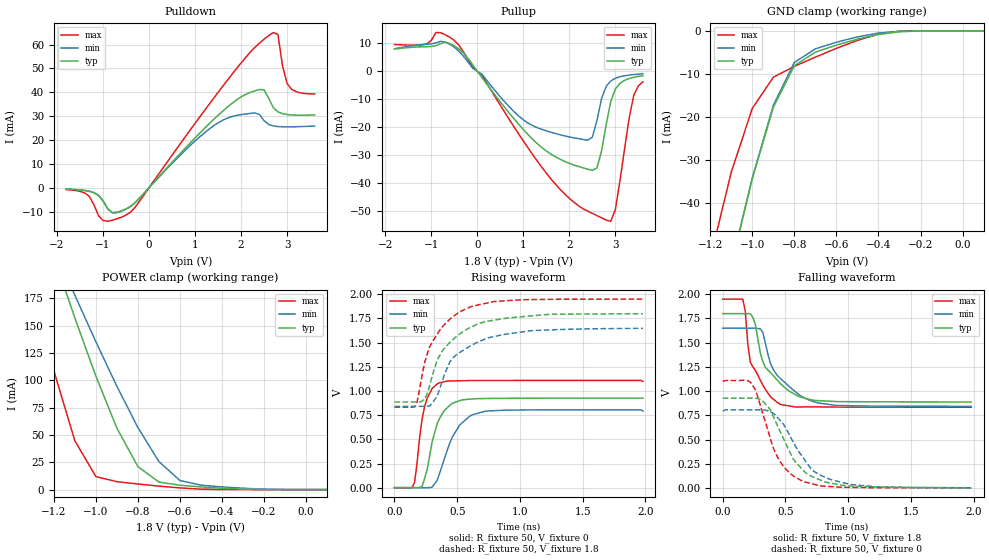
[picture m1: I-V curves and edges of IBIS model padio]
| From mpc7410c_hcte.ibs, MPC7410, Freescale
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| *   padio Model   *
[Model]   padio
Model_type   I/O
Polarity   Non-Inverting
Vinl = 0.63V
Vinh = 1.17V
Vmeas = 0.9V
Cref = 0
Rref = 50
Vref = 0.9V
|   typ   min   max
C_comp   2.563220e-12   2.204270e-12   2.663340e-12
|   typ   min   max
[Voltage range]   1.8V   1.65V   1.95V
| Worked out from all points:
|   slope of the pulldown table from 0 to 0.27 V, typ, clamps not added: 46.5 ohm
|   slope of the pullup table from 0 to 0.27 V, typ, clamps not added: 44.9 ohm
|   GND clamp passes 1 mA (typ) near -0.41 V on its own axis
|   POWER clamp passes 1 mA (typ) near -0.37 V on its own axis
|   falling waveform, R_fixture 50, V_fixture 1.8: 20-80 % time 196ps typ, 228ps min, 136ps max; typ from 1.8 V to 0.888 V
|   rising waveform, R_fixture 50, V_fixture 0: 20-80 % time 110ps typ, 151ps min, 73.6ps max; typ from 0.002 V to 0.926 V
|   falling waveform, R_fixture 50, V_fixture 0: 20-80 % time 237ps typ, 245ps min, 192ps max; typ from 0.926 V to 0.001 V
|   rising waveform, R_fixture 50, V_fixture 1.8: 20-80 % time 268ps typ, 278ps min, 223ps max; typ from 0.887 V to 1.8 V
[Pulldown]
|   Voltage   I(typ)   I(min)   I(max)
-1.8V     -606.8uA   -603.4uA   -802.4uA
-1.3V     -1.514mA   -1.486mA   -3.621mA
-1V       -5.639mA   -5.432mA   -13.74mA
-800mV    -10.41mA   -10.58mA   -13.67mA
-400mV    -7.822mA   -7.832mA   -10.21mA
1.5V      30.35mA    27.21mA    39.97mA
2.4V      41.16mA    30.67mA    60.6mA
2.7V      33.55mA    25.9mA     65.05mA
2.8V      31.81mA    25.64mA    64.3mA
2.9V      31.03mA    25.54mA    51.09mA
3V        30.66mA    25.51mA    43.69mA
3.6V      30.5mA     25.86mA    39.3mA
[GND_clamp]
-1.8V     -232mA     -232mA     -208.4mA
-1.2V     -76.69mA   -76.65mA   -52.94mA
-1.1V     -54.53mA   -54.43mA   -32.84mA
-1V       -34.39mA   -34.17mA   -18.02mA
-900mV    -17.76mA   -17.27mA   -10.79mA
-800mV    -8.1mA     -7.349mA   -8.261mA
-700mV    -4.948mA   -4.19mA    -6.115mA
-600mV    -3.315mA   -2.652mA   -4.077mA
-500mV    -1.938mA   -1.413mA   -2.223mA
-400mV    -849.8uA   -524.9uA   -765.8uA
-300mV    -218.8uA   -102.3uA   -83.96uA
100mV     0A         0A         0A
[Pullup]
-1.8V     7.912mA    8.018mA    9.503mA
-1.1V     8.739mA    9.607mA    9.735mA
-900mV    9.089mA    10.08mA    13.78mA
-500mV    9.035mA    8.552mA    10.97mA
1.1V      -22.59mA   -18.5mA    -27.33mA
1.9V      -32.2mA    -23.09mA   -43.83mA
2.5V      -35.4mA    -23.56mA   -50.72mA
2.7V      -28.47mA   -9.812mA   -52.34mA
2.9V      -10.78mA   -3.501mA   -53.57mA
3V        -6.349mA   -2.546mA   -49.42mA
3.4V      -2.185mA   -1.2mA     -8.597mA
3.6V      -1.636mA   -916.1uA   -3.783mA
[POWER_clamp]
-1.8V     573.2mA    491.9mA    598mA
-1.3V     271.2mA    265.4mA    183.9mA
-1.2V     213.2mA    221.2mA    108.8mA
-1.1V     157mA      177.7mA    44.67mA
-1V       103.7mA    135.2mA    11.86mA
-900mV    56.2mA     94.41mA    7.249mA
-800mV    20.97mA    56.73mA    5.115mA
-700mV    6.889mA    25.59mA    3.192mA
-600mV    4mA        8.298mA    1.547mA
-500mV    2.461mA    4.058mA    417.2uA
-300mV    412.1uA    1.268mA    2.246uA
100mV     0A         0A         0A
|   typ   min   max
[Ramp]
dV/dt_r   0.55489/1.10054e-10   0.48274/1.54952e-10   0.66523/7.35359e-11
dV/dt_f   0.54755/1.96657e-10   0.48461/2.28787e-10   0.66997/1.35857e-10
[Falling Waveform]
R_fixture = 50
V_fixture = 1.8
V_fixture_min = 1.65
V_fixture_max = 1.95
| time   V(typ)   V(min)   V(max)
0s        1.8V       1.65V      1.95V
160ps     1.8V       1.65V      1.949V
180ps     1.8V       1.65V      1.823V
220ps     1.8V       1.65V      1.299V
260ps     1.69V      1.651V     1.213V
320ps     1.304V     1.605V     1.061V
380ps     1.192V     1.29V      942.8mV
460ps     1.078V     1.13V      862.2mV
780ps     901.1mV    874.2mV    836.7mV
1.98ns    888.2mV    843.1mV    833.8mV
[Rising Waveform]
R_fixture = 50
V_fixture = 0
V_fixture_min = 0
V_fixture_max = 0
| time   V(typ)   V(min)   V(max)
0s        1.682mV    1.824mV    1.051mV
140ps     1.435mV    1.671mV    1.542mV
160ps     763.5uV    1.661mV    56.07mV
200ps     2.647mV    1.502mV    515.2mV
240ps     95.07mV    219.6uV    837mV
300ps     474.4mV    6.536mV    1.027V
360ps     719.1mV    149.6mV    1.086V
460ps     873.6mV    522.9mV    1.104V
620ps     918mV      754.6mV    1.109V
1.98ns    926.5mV    794.3mV    1.1V
[Falling Waveform]
R_fixture = 50
V_fixture = 0
V_fixture_min = 0
V_fixture_max = 0
| time   V(typ)   V(min)   V(max)
0s        926.5mV    794.3mV    1.1V
220ps     927.9mV    806.4mV    1.093V
260ps     928mV      807mV      1.015V
320ps     895.4mV    807.4mV    765.5mV
440ps     633mV      722.5mV    311.5mV
560ps     302.5mV    478.5mV    126.7mV
640ps     184.6mV    314mV      66.57mV
760ps     91.92mV    145.8mV    27.21mV
1.02ns    20.09mV    36.39mV    5.983mV
1.98ns    1.142mV    2.478mV    1.209mV
[Rising Waveform]
R_fixture = 50
V_fixture = 1.8
V_fixture_min = 1.65
V_fixture_max = 1.95
| time   V(typ)   V(min)   V(max)
0s        887.4mV    842.3mV    833.4mV
160ps     887.3mV    842.1mV    837.3mV
180ps     887.2mV    842.1mV    886mV
240ps     920.8mV    842mV      1.293V
280ps     1.057V     845.2mV    1.457V
380ps     1.412V     1.101V     1.662V
460ps     1.526V     1.336V     1.763V
600ps     1.654V     1.463V     1.867V
1.08ns    1.775V     1.623V     1.945V
1.98ns    1.799V     1.648V     1.95V
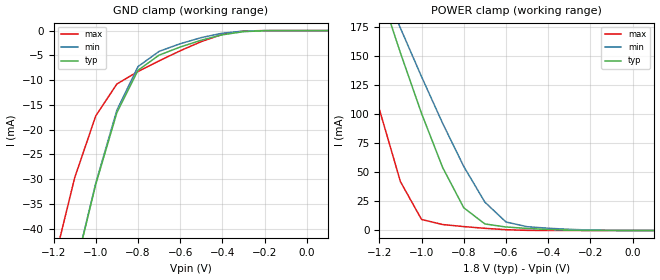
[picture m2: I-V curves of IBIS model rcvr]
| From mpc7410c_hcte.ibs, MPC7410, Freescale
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| *   rcvr  Model   *
[Model]   rcvr
Model_type   Input
Polarity   Non-Inverting
Vinl =   0.63V
Vinh =   1.17V
|   typ   min   max
C_comp   1.925330e-12   1.688180e-12   2.015310e-12
|   typ   min   max
[Voltage range]   1.8V   1.65V   1.95V
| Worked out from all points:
|   GND clamp passes 1 mA (typ) near -0.41 V on its own axis
|   POWER clamp passes 1 mA (typ) near -0.42 V on its own axis
|   Voltage(V)   I(typ)   I(min)   I(max)
[GND_clamp]
-1.8V     -206.6mA   -206.6mA   -185.7mA
-1.2V     -68.14mA   -68.09mA   -47.21mA
-1.1V     -48.65mA   -48.53mA   -29.75mA
-1V       -31.06mA   -30.82mA   -17.23mA
-900mV    -16.58mA   -16.09mA   -10.79mA
-800mV    -8.028mA   -7.275mA   -8.269mA
-700mV    -4.961mA   -4.205mA   -6.122mA
-600mV    -3.324mA   -2.661mA   -4.082mA
-500mV    -1.943mA   -1.418mA   -2.226mA
-400mV    -850.7uA   -525.9uA   -766.4uA
-300mV    -218uA     -102.2uA   -83.82uA
100mV     0A         0A         0A
[POWER_clamp]
-1.8V     558.2mA    481.7mA    575.9mA
-1.3V     263.9mA    259.8mA    176.5mA
-1.2V     207.3mA    216.4mA    104.1mA
-1.1V     152.4mA    173.7mA    41.87mA
-1V       100.4mA    132mA      9.452mA
-900mV    54.01mA    91.95mA    5.088mA
-800mV    19.47mA    54.94mA    3.343mA
-700mV    5.611mA    24.31mA    1.846mA
-600mV    2.992mA    7.272mA    672.4uA
-500mV    1.762mA    3.25mA     100.9uA
-400mV    842.2uA    1.923mA    4.444uA
100mV     0A         0A         0A
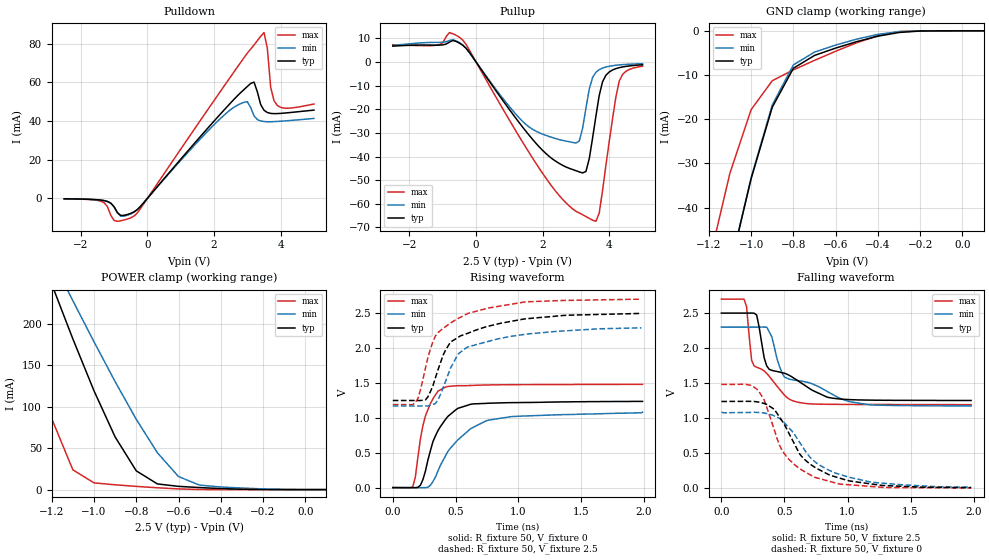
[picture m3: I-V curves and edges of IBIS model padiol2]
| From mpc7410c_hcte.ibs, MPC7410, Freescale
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| *   padiol2 Model   *
[Model]   padiol2
Model_type   I/O
Polarity   Non-Inverting
Vinl = 0.5V
Vinh = 1.7V
Vmeas = 1.25V
Cref = 0
Rref = 50
Vref = 1.25V
|   typ   min   max
C_comp   3.254250e-12   2.763960e-12   3.414570e-12
|   typ   min   max
[Voltage range]   2.5V   2.3V   2.7V
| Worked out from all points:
|   slope of the pulldown table from 0 to 0.375 V, typ, clamps not added: 49 ohm
|   slope of the pullup table from 0 to 0.375 V, typ, clamps not added: 48.7 ohm
|   GND clamp passes 1 mA (typ) near -0.37 V on its own axis
|   POWER clamp passes 1 mA (typ) near -0.37 V on its own axis
|   falling waveform, R_fixture 50, V_fixture 2.5: 20-80 % time 329ps typ, 410ps min, 215ps max; typ from 2.5 V to 1.25 V
|   rising waveform, R_fixture 50, V_fixture 0: 20-80 % time 163ps typ, 288ps min, 105ps max; typ from 0.005 V to 1.24 V
|   falling waveform, R_fixture 50, V_fixture 0: 20-80 % time 317ps typ, 357ps min, 251ps max; typ from 1.24 V to 0.005 V
|   rising waveform, R_fixture 50, V_fixture 2.5: 20-80 % time 321ps typ, 306ps min, 264ps max; typ from 1.25 V to 2.5 V
[Pulldown]
|   Voltage   I(typ)   I(min)   I(max)
-2.5V     -260uA     -268.5uA   -282.1uA
-1.4V     -921.3uA   -942.8uA   -1.479mA
-1V       -4.424mA   -4.438mA   -11.5mA
-400mV    -6.972mA   -7.174mA   -9.142mA
2.3V      45.69mA    43.02mA    58.06mA
3.1V      59.45mA    46.96mA    77.25mA
3.2V      60.15mA    42.67mA    79.38mA
3.5V      45.58mA    39.74mA    85.8mA
3.6V      44.41mA    39.64mA    77.59mA
3.7V      43.96mA    39.64mA    57.51mA
3.8V      43.84mA    39.7mA     50.53mA
5V        45.66mA    41.35mA    48.81mA
[GND_clamp]
-2.5V     -444.3mA   -444.4mA   -422.2mA
-1.2V     -76.28mA   -76.24mA   -52.5mA
-1.1V     -53.65mA   -53.55mA   -32.15mA
-1V       -33.47mA   -33.24mA   -17.84mA
-900mV    -17.28mA   -16.78mA   -11.3mA
-800mV    -8.466mA   -7.71mA    -8.841mA
-700mV    -5.569mA   -4.812mA   -6.686mA
-500mV    -2.446mA   -1.874mA   -2.695mA
-400mV    -1.214mA   -809uA     -1.086mA
-300mV    -374.1uA   -188.3uA   -155uA
-200mV    -45.67uA   -17.3uA    -4.049uA
100mV     0A         0A         0A
[Pullup]
-2.5V     6.689mA    6.969mA    7.264mA
-1.1V     7.122mA    8.279mA    7.326mA
-800mV    8.376mA    9.093mA    12.43mA
-400mV    7.078mA    7.178mA    9.265mA
1.5V      -29.35mA   -26.45mA   -36.22mA
3V        -45.99mA   -34.28mA   -63.16mA
3.1V      -46.5mA    -33.46mA   -63.86mA
3.3V      -46.31mA   -19.57mA   -65.39mA
3.6V      -22.9mA    -4.357mA   -67.39mA
3.8V      -8.333mA   -2.57mA    -54.2mA
4.3V      -2.416mA   -1.258mA   -8.071mA
5V        -1.206mA   -745uA     -1.822mA
[POWER_clamp]
-2.5V     1.179A     961.8mA    1.389A
-1.4V     385.1mA    380.9mA    264.3mA
-1.3V     315.7mA    329.3mA    170.7mA
-1.2V     247.6mA    278.1mA    85.59mA
-1.1V     181.6mA    227.7mA    23.86mA
-1V       119.1mA    178.2mA    8.146mA
-900mV    63.49mA    130.2mA    5.772mA
-800mV    22.65mA    84.74mA    3.887mA
-700mV    6.851mA    44.46mA    2.193mA
-600mV    3.911mA    15.69mA    841.7uA
-500mV    2.443mA    5.408mA    137.3uA
100mV     0A         0A         0A
|   typ   min   max
[Ramp]
dV/dt_r   0.73948/1.62740e-10   0.64172/2.80672e-10   0.88709/1.04552e-10
dV/dt_f   0.75015/3.30448e-10   0.67683/4.10006e-10   0.90483/2.13989e-10
[Falling Waveform]
R_fixture = 50
V_fixture = 2.5
V_fixture_min = 2.3
V_fixture_max = 2.7
| time   V(typ)   V(min)   V(max)
0s        2.5V       2.3V       2.7V
180ps     2.5V       2.3V       2.7V
200ps     2.5V       2.3V       2.592V
240ps     2.501V     2.3V       1.825V
280ps     2.472V     2.3V       1.726V
360ps     1.744V     2.299V     1.638V
480ps     1.649V     1.647V     1.371V
560ps     1.588V     1.548V     1.252V
880ps     1.284V     1.339V     1.196V
1.98ns    1.251V     1.173V     1.192V
[Rising Waveform]
R_fixture = 50
V_fixture = 0
V_fixture_min = 0
V_fixture_max = 0
| time   V(typ)   V(min)   V(max)
0s        4.766mV    5.07mV     2.27mV
160ps     2.982mV    3.882mV    18.98mV
180ps     2.373mV    3.75mV     157.1mV
220ps     37.02mV    2.641mV    697.8mV
260ps     238.4mV    3.926mV    1.028V
320ps     661.4mV    90.76mV    1.275V
420ps     979.7mV    457.8mV    1.441V
520ps     1.139V     689.1mV    1.462V
760ps     1.211V     968.6mV    1.472V
1.99ns    1.237V     1.084V     1.481V
[Falling Waveform]
R_fixture = 50
V_fixture = 0
V_fixture_min = 0
V_fixture_max = 0
| time   V(typ)   V(min)   V(max)
0s        1.237V     1.084V     1.481V
280ps     1.232V     1.081V     1.416V
340ps     1.208V     1.072V     1.255V
420ps     1.124V     1.03V      831mV
480ps     961.5mV    969.2mV    542.1mV
620ps     488.3mV    654.6mV    277mV
740ps     296.8mV    377.4mV    152.7mV
900ps     161.8mV    216.5mV    73.91mV
1.18ns    59.68mV    85.92mV    23.08mV
1.98ns    4.576mV    11.26mV    1.961mV
[Rising Waveform]
R_fixture = 50
V_fixture = 2.5
V_fixture_min = 2.3
V_fixture_max = 2.7
| time   V(typ)   V(min)   V(max)
0s        1.25V      1.172V     1.192V
160ps     1.25V      1.172V     1.191V
200ps     1.249V     1.172V     1.277V
280ps     1.303V     1.172V     1.867V
340ps     1.577V     1.207V     2.174V
460ps     2.085V     1.712V     2.358V
520ps     2.153V     1.913V     2.422V
600ps     2.213V     2.017V     2.496V
1.06ns    2.419V     2.199V     2.662V
1.98ns    2.496V     2.289V     2.7V
